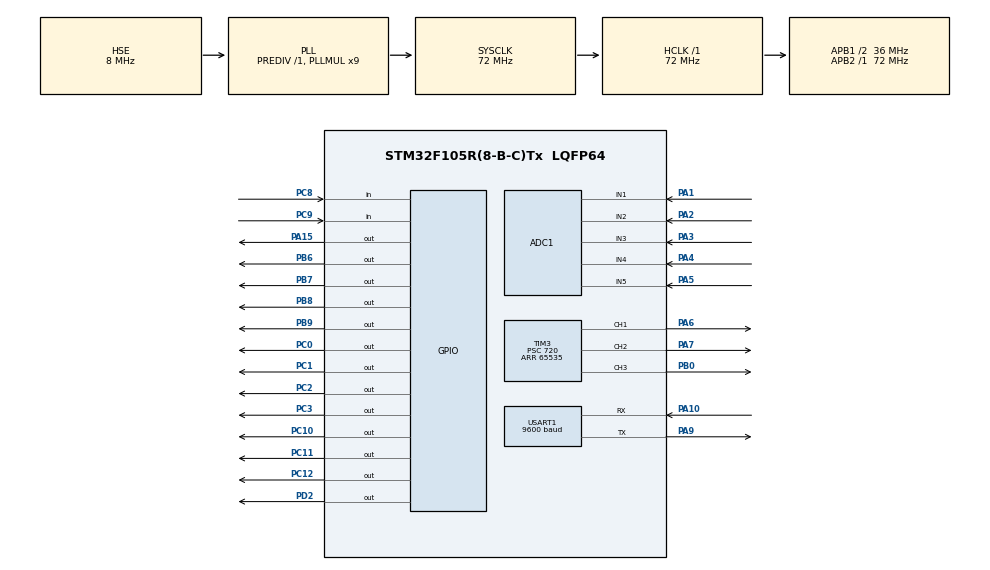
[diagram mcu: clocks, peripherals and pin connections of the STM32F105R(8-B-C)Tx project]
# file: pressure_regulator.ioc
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ADC1.Channel-1\#ChannelInjectedConversion=ADC_CHANNEL_1
ADC1.Channel-2\#ChannelInjectedConversion=ADC_CHANNEL_2
ADC1.Channel-3\#ChannelInjectedConversion=ADC_CHANNEL_3
ADC1.Channel-4\#ChannelInjectedConversion=ADC_CHANNEL_4
ADC1.EnableRegularConversion=DISABLE
ADC1.InjNumberOfConversion=4
ADC1.InjectedOffset-1\#ChannelInjectedConversion=0
ADC1.InjectedOffset-2\#ChannelInjectedConversion=0
ADC1.InjectedOffset-3\#ChannelInjectedConversion=0
ADC1.InjectedOffset-4\#ChannelInjectedConversion=0
ADC1.Rank-1\#ChannelInjectedConversion=1
ADC1.Rank-2\#ChannelInjectedConversion=2
ADC1.Rank-3\#ChannelInjectedConversion=3
ADC1.Rank-4\#ChannelInjectedConversion=4
ADC1.SamplingTime-1\#ChannelInjectedConversion=ADC_SAMPLETIME_71CYCLES_5
ADC1.SamplingTime-2\#ChannelInjectedConversion=ADC_SAMPLETIME_71CYCLES_5
ADC1.SamplingTime-3\#ChannelInjectedConversion=ADC_SAMPLETIME_71CYCLES_5
ADC1.SamplingTime-4\#ChannelInjectedConversion=ADC_SAMPLETIME_71CYCLES_5
ADC1.master=1
Dma.Request0=USART1_TX
Dma.USART1_TX.0.Direction=DMA_MEMORY_TO_PERIPH
Dma.USART1_TX.0.Instance=DMA1_Channel4
Dma.USART1_TX.0.MemDataAlignment=DMA_MDATAALIGN_BYTE
Dma.USART1_TX.0.MemInc=DMA_MINC_ENABLE
Dma.USART1_TX.0.Mode=DMA_NORMAL
Dma.USART1_TX.0.PeriphDataAlignment=DMA_PDATAALIGN_BYTE
Dma.USART1_TX.0.PeriphInc=DMA_PINC_DISABLE
Dma.USART1_TX.0.Priority=DMA_PRIORITY_MEDIUM
FREERTOS.Tasks01=defaultTask,0,128,StartDefaultTask,Default,NULL
FREERTOS.configTOTAL_HEAP_SIZE=20000
Mcu.Family=STM32F1
Mcu.Name=STM32F105R(8-B-C)Tx
Mcu.Package=LQFP64
NVIC.ADC1_2_IRQn=true\:5\:0\:false\:false\:true\:true\:true\:true
NVIC.DMA1_Channel4_IRQn=true\:5\:0\:false\:false\:true\:true\:false\:true
NVIC.PriorityGroup=NVIC_PRIORITYGROUP_4
NVIC.TIM3_IRQn=true\:5\:0\:false\:false\:true\:true\:true\:true
NVIC.USART1_IRQn=true\:5\:0\:false\:false\:true\:true\:true\:true
PA1.Signal=ADCx_IN1
PA10.Mode=Asynchronous
PA10.Signal=USART1_RX
PA13.Mode=Serial_Wire
PA13.Signal=SYS_JTMS-SWDIO
PA14.Mode=Serial_Wire
PA14.Signal=SYS_JTCK-SWCLK
PA15.Signal=GPIO_Output
PA2.Signal=ADCx_IN2
PA3.Signal=ADCx_IN3
PA4.Signal=ADCx_IN4
PA5.Signal=ADCx_IN5
PA6.Signal=S_TIM3_CH1
PA7.Signal=S_TIM3_CH2
PA9.Mode=Asynchronous
PA9.Signal=USART1_TX
PB0.Signal=S_TIM3_CH3
PB6.GPIO_Speed=GPIO_SPEED_FREQ_MEDIUM
PB6.Signal=GPIO_Output
PB7.GPIO_Speed=GPIO_SPEED_FREQ_MEDIUM
PB7.Signal=GPIO_Output
PB8.GPIO_Speed=GPIO_SPEED_FREQ_MEDIUM
PB8.Signal=GPIO_Output
PB9.GPIO_Speed=GPIO_SPEED_FREQ_MEDIUM
PB9.Signal=GPIO_Output
PC0.GPIO_Speed=GPIO_SPEED_FREQ_MEDIUM
PC0.Signal=GPIO_Output
PC1.GPIO_Speed=GPIO_SPEED_FREQ_MEDIUM
PC1.Signal=GPIO_Output
PC10.GPIO_Speed=GPIO_SPEED_FREQ_MEDIUM
PC10.Signal=GPIO_Output
PC11.GPIO_Speed=GPIO_SPEED_FREQ_MEDIUM
PC11.Signal=GPIO_Output
PC12.GPIO_Speed=GPIO_SPEED_FREQ_MEDIUM
PC12.Signal=GPIO_Output
PC2.GPIO_Speed=GPIO_SPEED_FREQ_MEDIUM
PC2.Signal=GPIO_Output
PC3.GPIO_Speed=GPIO_SPEED_FREQ_MEDIUM
PC3.Signal=GPIO_Output
PC8.Signal=GPIO_Input
PC9.Signal=GPIO_Input
PD0-OSC_IN.Mode=HSE-External-Oscillator
PD0-OSC_IN.Signal=RCC_OSC_IN
PD1-OSC_OUT.Mode=HSE-External-Oscillator
PD1-OSC_OUT.Signal=RCC_OSC_OUT
PD2.GPIO_Speed=GPIO_SPEED_FREQ_MEDIUM
PD2.PinState=GPIO_PIN_SET
PD2.Signal=GPIO_Output
ProjectManager.HeapSize=0x200
ProjectManager.StackSize=0x400
ProjectManager.TargetToolchain=TrueSTUDIO
RCC.ADCPresc=RCC_ADCPCLK2_DIV6
RCC.AHBFreq_Value=72000000
RCC.APB1CLKDivider=RCC_HCLK_DIV2
RCC.APB1Freq_Value=36000000
RCC.APB1TimFreq_Value=72000000
RCC.APB2Freq_Value=72000000
RCC.APB2TimFreq_Value=72000000
RCC.HCLKFreq_Value=72000000
RCC.PLLMUL=RCC_PLL_MUL9
RCC.PLLSourceVirtual=RCC_PLLSOURCE_HSE
RCC.SYSCLKFreq_VALUE=72000000
RCC.SYSCLKSource=RCC_SYSCLKSOURCE_PLLCLK
RCC.USBFreq_Value=48000000
SH.ADCx_IN1.0=ADC1_IN1,IN1
SH.ADCx_IN2.0=ADC1_IN2,IN2
SH.ADCx_IN3.0=ADC1_IN3,IN3
SH.ADCx_IN4.0=ADC1_IN4,IN4
SH.ADCx_IN5.0=ADC1_IN5,IN5
SH.S_TIM3_CH1.0=TIM3_CH1,PWM Generation1 CH1
SH.S_TIM3_CH2.0=TIM3_CH2,PWM Generation2 CH2
SH.S_TIM3_CH3.0=TIM3_CH3,PWM Generation3 CH3
TIM3.Channel-PWM\ Generation1\ CH1=TIM_CHANNEL_1
TIM3.Channel-PWM\ Generation2\ CH2=TIM_CHANNEL_2
TIM3.Channel-PWM\ Generation3\ CH3=TIM_CHANNEL_3
TIM3.Period=65535
TIM3.Prescaler=720
USART1.BaudRate=9600
USART1.VirtualMode=VM_ASYNC
VP_FREERTOS_VS_CMSIS_V1.Mode=CMSIS_V1
board=custom

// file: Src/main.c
/* USER CODE BEGIN Header */
/**
  ******************************************************************************
  * @file           : main.c
  * @brief          : Main program body
  ******************************************************************************
  * @attention
  *
  * <h2><center>&copy; Copyright (c) 2019 STMicroelectronics.
  * All rights reserved.</center></h2>
  *
  * This software component is licensed by ST under Ultimate Liberty license
  * SLA0044, the "License"; You may not use this file except in compliance with
  * the License. You may obtain a copy of the License at:
  *                             www.st.com/SLA0044
  *
  ******************************************************************************
  */
/* USER CODE END Header */

#include "main.h"
#include "cmsis_os.h"

/* USER CODE BEGIN Includes */
#include "structures.h"
#include "controllerInit.h"
#include "useful.h"

/* USER CODE END Includes */

ADC_HandleTypeDef hadc1;

TIM_HandleTypeDef htim3;

UART_HandleTypeDef huart1;
DMA_HandleTypeDef hdma_usart1_tx;

osThreadId defaultTaskHandle;
/* USER CODE BEGIN PV */

GPIO_TypeDef * UP_PORT[4] = {C1_UP_PORT, C2_UP_PORT, C3_UP_PORT, C4_UP_PORT};
uint32_t UP_PIN[4] = {C1_UP_PIN, C2_UP_PIN, C3_UP_PIN, C4_UP_PIN};
GPIO_TypeDef * DOWN_PORT[4] = {C1_DOWN_PORT, C2_DOWN_PORT, C3_DOWN_PORT, C4_DOWN_PORT};
uint32_t DOWN_PIN[4] = {C1_DOWN_PIN, C2_DOWN_PIN, C3_DOWN_PIN, C4_DOWN_PIN};

uint16_t ADCRawData[4];
uint16_t sensorValue[4];

char message[128] = {0};

uint8_t recCommandBuffer[MAX_COMMAND_LENGTH];
uint8_t p_recCommandBuffer;
uint8_t recCommandByte;
uint8_t commandToProcessBuffer[MAX_COMMAND_LENGTH];
uint8_t p_commandToProcessBuffer;

uint16_t nessPressure[4] = {0};
uint16_t server_UID = 0;

struct controllerData controllerSettings = {0};

//struct Filtered filteredData = {0};
uint16_t filteredPressure[4] = {1,2,3,4};

enum WorkState workState = FREE;
enum Compensation pressureCompensation = OFF;

xQueueHandle xRecCommandQueue;
xSemaphoreHandle xPressureCompensationSemaphore;

/* USER CODE END PV */

void SystemClock_Config(void);
static void MX_GPIO_Init(void);
static void MX_DMA_Init(void);
static void MX_ADC1_Init(void);
static void MX_USART1_UART_Init(void);
static void MX_TIM3_Init(void);
void StartDefaultTask(void const * argument);

int main(void)
{

  /* MCU Configuration--------------------------------------------------------*/

  /* Reset of all peripherals, Initializes the Flash interface and the Systick. */
  HAL_Init();

  /* Configure the system clock */
  SystemClock_Config();

  /* Initialize all configured peripherals */
  MX_GPIO_Init();
  MX_DMA_Init();
  MX_ADC1_Init();
  MX_USART1_UART_Init();
  MX_TIM3_Init();
  /* USER CODE BEGIN 2 */
  //init_rf433();
  /* USER CODE END 2 */

  /* Create the thread(s) */
  /* definition and creation of defaultTask */
  osThreadDef(defaultTask, StartDefaultTask, osPriorityNormal, 0, 128);
  defaultTaskHandle = osThreadCreate(osThread(defaultTask), NULL);

  /* USER CODE BEGIN RTOS_THREADS */
  /* add threads, ... */
  controller_initialize();
  /* USER CODE END RTOS_THREADS */

  /* Start scheduler */
  osKernelStart();

  /* We should never get here as control is now taken by the scheduler */

  /* Infinite loop */
  while (1)
  {

  }
}

void SystemClock_Config(void)
{
  RCC_OscInitTypeDef RCC_OscInitStruct = {0};
  RCC_ClkInitTypeDef RCC_ClkInitStruct = {0};
  RCC_PeriphCLKInitTypeDef PeriphClkInit = {0};

  /** Initializes the CPU, AHB and APB busses clocks
  */
  RCC_OscInitStruct.OscillatorType = RCC_OSCILLATORTYPE_HSE;
  RCC_OscInitStruct.HSEState = RCC_HSE_ON;
  RCC_OscInitStruct.HSEPredivValue = RCC_HSE_PREDIV_DIV1;
  RCC_OscInitStruct.HSIState = RCC_HSI_ON;
  RCC_OscInitStruct.Prediv1Source = RCC_PREDIV1_SOURCE_HSE;
  RCC_OscInitStruct.PLL.PLLState = RCC_PLL_ON;
  RCC_OscInitStruct.PLL.PLLSource = RCC_PLLSOURCE_HSE;
  RCC_OscInitStruct.PLL.PLLMUL = RCC_PLL_MUL9;
  RCC_OscInitStruct.PLL2.PLL2State = RCC_PLL_NONE;
  if (HAL_RCC_OscConfig(&RCC_OscInitStruct) != HAL_OK)
  {
    Error_Handler();
  }
  /** Initializes the CPU, AHB and APB busses clocks
  */
  RCC_ClkInitStruct.ClockType = RCC_CLOCKTYPE_HCLK|RCC_CLOCKTYPE_SYSCLK
                              |RCC_CLOCKTYPE_PCLK1|RCC_CLOCKTYPE_PCLK2;
  RCC_ClkInitStruct.SYSCLKSource = RCC_SYSCLKSOURCE_PLLCLK;
  RCC_ClkInitStruct.AHBCLKDivider = RCC_SYSCLK_DIV1;
  RCC_ClkInitStruct.APB1CLKDivider = RCC_HCLK_DIV2;
  RCC_ClkInitStruct.APB2CLKDivider = RCC_HCLK_DIV1;

  if (HAL_RCC_ClockConfig(&RCC_ClkInitStruct, FLASH_LATENCY_2) != HAL_OK)
  {
    Error_Handler();
  }
  PeriphClkInit.PeriphClockSelection = RCC_PERIPHCLK_ADC;
  PeriphClkInit.AdcClockSelection = RCC_ADCPCLK2_DIV6;
  if (HAL_RCCEx_PeriphCLKConfig(&PeriphClkInit) != HAL_OK)
  {
    Error_Handler();
  }
  /** Configure the Systick interrupt time
  */
  __HAL_RCC_PLLI2S_ENABLE();
}

static void MX_ADC1_Init(void)
{

  ADC_InjectionConfTypeDef sConfigInjected = {0};

  /** Common config
  */
  hadc1.Instance = ADC1;
  hadc1.Init.ScanConvMode = ADC_SCAN_ENABLE;
  hadc1.Init.ContinuousConvMode = DISABLE;
  hadc1.Init.DiscontinuousConvMode = DISABLE;
  hadc1.Init.ExternalTrigConv = ADC_SOFTWARE_START;
  hadc1.Init.DataAlign = ADC_DATAALIGN_RIGHT;
  hadc1.Init.NbrOfConversion = 1;
  if (HAL_ADC_Init(&hadc1) != HAL_OK)
  {
    Error_Handler();
  }
  /** Configure Injected Channel
  */

  /* USER CODE BEGIN ADC1_Init 2 */
  sConfigInjected.InjectedChannel = ADC_CHANNEL_0;
  sConfigInjected.InjectedRank = ADC_INJECTED_RANK_1;
  sConfigInjected.InjectedNbrOfConversion = 4;
  sConfigInjected.InjectedSamplingTime = ADC_SAMPLETIME_71CYCLES_5;
  sConfigInjected.ExternalTrigInjecConv = ADC_INJECTED_SOFTWARE_START;
  sConfigInjected.AutoInjectedConv = DISABLE;
  sConfigInjected.InjectedDiscontinuousConvMode = DISABLE;
  sConfigInjected.InjectedOffset = 0;
  if (HAL_ADCEx_InjectedConfigChannel(&hadc1, &sConfigInjected) != HAL_OK)
  {
    Error_Handler();
  }
  /** Configure Injected Channel
  */
  sConfigInjected.InjectedChannel = ADC_CHANNEL_1;
  sConfigInjected.InjectedRank = ADC_INJECTED_RANK_2;
  if (HAL_ADCEx_InjectedConfigChannel(&hadc1, &sConfigInjected) != HAL_OK)
  {
    Error_Handler();
  }
  /** Configure Injected Channel
  */
  sConfigInjected.InjectedChannel = ADC_CHANNEL_2;
  sConfigInjected.InjectedRank = ADC_INJECTED_RANK_3;
  if (HAL_ADCEx_InjectedConfigChannel(&hadc1, &sConfigInjected) != HAL_OK)
  {
    Error_Handler();
  }
  /** Configure Injected Channel
  */
  sConfigInjected.InjectedChannel = ADC_CHANNEL_3;
  sConfigInjected.InjectedRank = ADC_INJECTED_RANK_4;
  if (HAL_ADCEx_InjectedConfigChannel(&hadc1, &sConfigInjected) != HAL_OK)
  {
    Error_Handler();
  }
  /* USER CODE END ADC1_Init 2 */

}

static void MX_TIM3_Init(void)
{

  TIM_MasterConfigTypeDef sMasterConfig = {0};
  TIM_OC_InitTypeDef sConfigOC = {0};

  htim3.Instance = TIM3;
  htim3.Init.Prescaler = 720;
  htim3.Init.CounterMode = TIM_COUNTERMODE_UP;
  htim3.Init.Period = 65535;
  htim3.Init.ClockDivision = TIM_CLOCKDIVISION_DIV1;
  htim3.Init.AutoReloadPreload = TIM_AUTORELOAD_PRELOAD_DISABLE;
  if (HAL_TIM_PWM_Init(&htim3) != HAL_OK)
  {
    Error_Handler();
  }
  sMasterConfig.MasterOutputTrigger = TIM_TRGO_RESET;
  sMasterConfig.MasterSlaveMode = TIM_MASTERSLAVEMODE_DISABLE;
  if (HAL_TIMEx_MasterConfigSynchronization(&htim3, &sMasterConfig) != HAL_OK)
  {
    Error_Handler();
  }
  sConfigOC.OCMode = TIM_OCMODE_PWM1;
  sConfigOC.Pulse = 0;
  sConfigOC.OCPolarity = TIM_OCPOLARITY_HIGH;
  sConfigOC.OCFastMode = TIM_OCFAST_DISABLE;
  if (HAL_TIM_PWM_ConfigChannel(&htim3, &sConfigOC, TIM_CHANNEL_1) != HAL_OK)
  {
    Error_Handler();
  }
  if (HAL_TIM_PWM_ConfigChannel(&htim3, &sConfigOC, TIM_CHANNEL_2) != HAL_OK)
  {
    Error_Handler();
  }
  if (HAL_TIM_PWM_ConfigChannel(&htim3, &sConfigOC, TIM_CHANNEL_3) != HAL_OK)
  {
    Error_Handler();
  }
  HAL_TIM_MspPostInit(&htim3);

}

static void MX_USART1_UART_Init(void)
{

  huart1.Instance = USART1;
  huart1.Init.BaudRate = 9600;
  huart1.Init.WordLength = UART_WORDLENGTH_8B;
  huart1.Init.StopBits = UART_STOPBITS_1;
  huart1.Init.Parity = UART_PARITY_NONE;
  huart1.Init.Mode = UART_MODE_TX_RX;
  huart1.Init.HwFlowCtl = UART_HWCONTROL_NONE;
  huart1.Init.OverSampling = UART_OVERSAMPLING_16;
  if (HAL_UART_Init(&huart1) != HAL_OK)
  {
    Error_Handler();
  }

}

static void MX_DMA_Init(void)
{
  /* DMA controller clock enable */
  __HAL_RCC_DMA1_CLK_ENABLE();

  /* DMA interrupt init */
  /* DMA1_Channel4_IRQn interrupt configuration */
  HAL_NVIC_SetPriority(DMA1_Channel4_IRQn, 5, 0);
  HAL_NVIC_EnableIRQ(DMA1_Channel4_IRQn);

}

static void MX_GPIO_Init(void)
{
  GPIO_InitTypeDef GPIO_InitStruct = {0};

  /* GPIO Ports Clock Enable */
  __HAL_RCC_GPIOD_CLK_ENABLE();
  __HAL_RCC_GPIOC_CLK_ENABLE();
  __HAL_RCC_GPIOA_CLK_ENABLE();
  __HAL_RCC_GPIOB_CLK_ENABLE();

  /*Configure GPIO pin Output Level */

  /*Configure GPIO pin Output Level */
  HAL_GPIO_WritePin(GPIOA, GPIO_PIN_11, GPIO_PIN_SET);

  /*Configure GPIO pin Output Level */
  HAL_GPIO_WritePin(GPIOD, GPIO_PIN_2, GPIO_PIN_RESET);

  /*Configure GPIO pin Output Level */
  HAL_GPIO_WritePin(GPIOB, GPIO_PIN_9|GPIO_PIN_8|GPIO_PIN_7|GPIO_PIN_6|GPIO_PIN_5|GPIO_PIN_4|GPIO_PIN_3, GPIO_PIN_RESET);

  GPIO_InitStruct.Pin = GPIO_PIN_9|GPIO_PIN_8|GPIO_PIN_7|GPIO_PIN_6|GPIO_PIN_5|GPIO_PIN_4|GPIO_PIN_3;
  GPIO_InitStruct.Mode = GPIO_MODE_OUTPUT_PP;
  GPIO_InitStruct.Pull = GPIO_NOPULL;
  GPIO_InitStruct.Speed = GPIO_SPEED_FREQ_MEDIUM;
  HAL_GPIO_Init(GPIOB, &GPIO_InitStruct);

  GPIO_InitStruct.Pin = GPIO_PIN_2;
  GPIO_InitStruct.Mode = GPIO_MODE_OUTPUT_PP;
  GPIO_InitStruct.Pull = GPIO_NOPULL;
  GPIO_InitStruct.Speed = GPIO_SPEED_FREQ_MEDIUM;
  HAL_GPIO_Init(GPIOD, &GPIO_InitStruct);

  GPIO_InitStruct.Pin = GPIO_PIN_8;
  GPIO_InitStruct.Mode = GPIO_MODE_INPUT;
  GPIO_InitStruct.Pull = GPIO_NOPULL;
  HAL_GPIO_Init(GPIOA, &GPIO_InitStruct);

  GPIO_InitStruct.Pin = GPIO_PIN_11;
  GPIO_InitStruct.Mode = GPIO_MODE_OUTPUT_PP;
  GPIO_InitStruct.Pull = GPIO_NOPULL;
  GPIO_InitStruct.Speed = GPIO_SPEED_FREQ_MEDIUM;
  HAL_GPIO_Init(GPIOA, &GPIO_InitStruct);

}

/* USER CODE BEGIN 4 */

void HAL_UART_RxCpltCallback(UART_HandleTypeDef *huart){
	if(huart->Instance == USART1){
		if (recCommandByte != '\r'){
			recCommandBuffer[p_recCommandBuffer] = recCommandByte;
			p_recCommandBuffer++;

			if (p_recCommandBuffer == MAX_COMMAND_LENGTH) p_recCommandBuffer = 0;

			if(recCommandByte == '\n'){
				memcpy(commandToProcessBuffer, recCommandBuffer, p_recCommandBuffer);
				portBASE_TYPE r1;
				xQueueSendToBackFromISR(xRecCommandQueue, &commandToProcessBuffer, &r1);
				p_recCommandBuffer = 0;
			}
			else if (recCommandByte == 0xFF) {
				p_recCommandBuffer = 0;
			}
		}

		HAL_UART_Receive_IT(&huart1, &recCommandByte, 1);
	}
}

void HAL_ADCEx_InjectedConvCpltCallback(ADC_HandleTypeDef* hadc1){
	  ADCRawData[0]=HAL_ADCEx_InjectedGetValue(hadc1,ADC_INJECTED_RANK_1);
	  ADCRawData[1]=HAL_ADCEx_InjectedGetValue(hadc1,ADC_INJECTED_RANK_2);
	  ADCRawData[2]=HAL_ADCEx_InjectedGetValue(hadc1,ADC_INJECTED_RANK_3);
	  ADCRawData[3]=HAL_ADCEx_InjectedGetValue(hadc1,ADC_INJECTED_RANK_4);
}
/* USER CODE END 4 */

void StartDefaultTask(void const * argument)
{

  for(;;)
  {
    osDelay(1);
  }
}

void Error_Handler(void)
{
}

/************************ (C) COPYRIGHT STMicroelectronics *****END OF FILE****/
